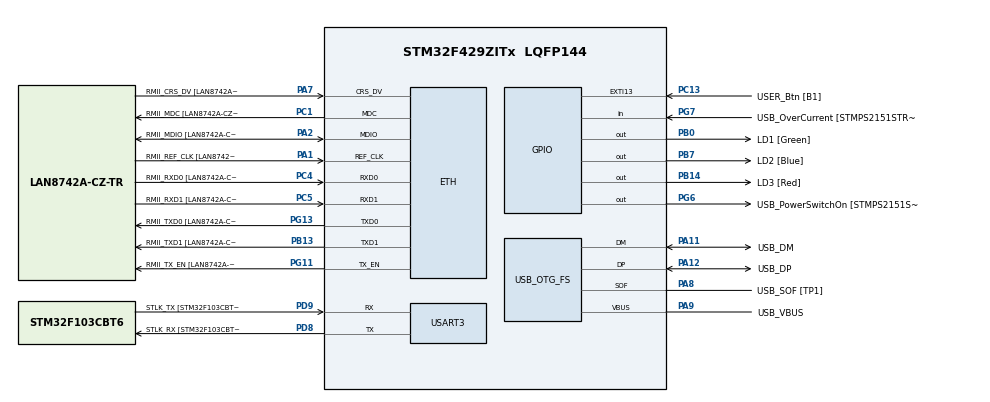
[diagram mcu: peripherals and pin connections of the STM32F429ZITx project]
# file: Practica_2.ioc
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ETH.MediaInterface=HAL_ETH_RMII_MODE
ETH.PHY_Name=LAN8742A_PHY_ADDRESS
ETH.PHY_Value=0
ETH.PhyAddress=0
Mcu.Family=STM32F4
Mcu.Name=STM32F429ZITx
Mcu.Package=LQFP144
NVIC.PriorityGroup=NVIC_PRIORITYGROUP_4
PA1.GPIO_Label=RMII_REF_CLK [LAN8742A-CZ-TR_REFCLK0]
PA1.Mode=RMII
PA1.Signal=ETH_REF_CLK
PA10.GPIO_Label=USB_ID
PA10.Signal=USB_OTG_FS_ID
PA11.GPIO_Label=USB_DM
PA11.Mode=Device_Only
PA11.Signal=USB_OTG_FS_DM
PA12.GPIO_Label=USB_DP
PA12.Mode=Device_Only
PA12.Signal=USB_OTG_FS_DP
PA13.GPIO_Label=TMS
PA13.Mode=Serial_Wire
PA13.Signal=SYS_JTMS-SWDIO
PA14.GPIO_Label=TCK
PA14.Mode=Serial_Wire
PA14.Signal=SYS_JTCK-SWCLK
PA2.GPIO_Label=RMII_MDIO [LAN8742A-CZ-TR_MDIO]
PA2.Mode=RMII
PA2.Signal=ETH_MDIO
PA7.GPIO_Label=RMII_CRS_DV [LAN8742A-CZ-TR_CRS_DV]
PA7.Mode=RMII
PA7.Signal=ETH_CRS_DV
PA8.GPIO_Label=USB_SOF [TP1]
PA8.Mode=Activate_SOF_FS
PA8.Signal=USB_OTG_FS_SOF
PA9.GPIO_Label=USB_VBUS
PA9.Mode=Activate_VBUS
PA9.Signal=USB_OTG_FS_VBUS
PB0.GPIO_Label=LD1 [Green]
PB0.Signal=GPIO_Output
PB13.GPIO_Label=RMII_TXD1 [LAN8742A-CZ-TR_TXD1]
PB13.Mode=RMII
PB13.Signal=ETH_TXD1
PB14.GPIO_Label=LD3 [Red]
PB14.Signal=GPIO_Output
PB7.GPIO_Label=LD2 [Blue]
PB7.Signal=GPIO_Output
PC1.GPIO_Label=RMII_MDC [LAN8742A-CZ-TR_MDC]
PC1.Mode=RMII
PC1.Signal=ETH_MDC
PC13.GPIO_Label=USER_Btn [B1]
PC13.Signal=GPXTI13
PC14/OSC32_IN.Mode=LSE-External-Oscillator
PC14/OSC32_IN.Signal=RCC_OSC32_IN
PC15/OSC32_OUT.Mode=LSE-External-Oscillator
PC15/OSC32_OUT.Signal=RCC_OSC32_OUT
PC4.GPIO_Label=RMII_RXD0 [LAN8742A-CZ-TR_RXD0]
PC4.Mode=RMII
PC4.Signal=ETH_RXD0
PC5.GPIO_Label=RMII_RXD1 [LAN8742A-CZ-TR_RXD1]
PC5.Mode=RMII
PC5.Signal=ETH_RXD1
PD8.GPIO_Label=STLK_RX [STM32F103CBT6_PA3]
PD8.Mode=Asynchronous
PD8.Signal=USART3_TX
PD9.GPIO_Label=STLK_TX [STM32F103CBT6_PA2]
PD9.Mode=Asynchronous
PD9.Signal=USART3_RX
PG11.GPIO_Label=RMII_TX_EN [LAN8742A-CZ-TR_TXEN]
PG11.Mode=RMII
PG11.Signal=ETH_TX_EN
PG13.GPIO_Label=RMII_TXD0 [LAN8742A-CZ-TR_TXD0]
PG13.Mode=RMII
PG13.Signal=ETH_TXD0
PG6.GPIO_Label=USB_PowerSwitchOn [STMPS2151STR_EN]
PG6.Signal=GPIO_Output
PG7.GPIO_Label=USB_OverCurrent [STMPS2151STR_FAULT]
PG7.Signal=GPIO_Input
PH0/OSC_IN.Mode=HSE-External-Clock-Source
PH0/OSC_IN.Signal=RCC_OSC_IN
PH1/OSC_OUT.Mode=HSE-External-Clock-Source
PH1/OSC_OUT.Signal=RCC_OSC_OUT
ProjectManager.HeapSize=0x200
ProjectManager.StackSize=0x400
ProjectManager.TargetToolchain=STM32CubeIDE
RCC.48MHZClocksFreq_Value=48000000
RCC.AHBFreq_Value=168000000
RCC.APB1Freq_Value=42000000
RCC.APB1TimFreq_Value=42000000
RCC.APB2Freq_Value=84000000
RCC.APB2TimFreq_Value=84000000
RCC.CortexFreq_Value=168000000
RCC.HCLKFreq_Value=168000000
RCC.HSE_VALUE=8000000
RCC.SYSCLKFreq_VALUE=168000000
RCC.SYSCLKSource=RCC_SYSCLKSOURCE_PLLCLK
RCC.VCOOutputFreq_Value=336000000
USART3.VirtualMode=VM_ASYNC
USB_OTG_FS.VirtualMode=Device_Only
board=NUCLEO-F429ZI

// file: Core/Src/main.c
/* USER CODE BEGIN Header */
/**
  ******************************************************************************
  * @file           : main.c
  * @brief          : Main program body
  ******************************************************************************
  * @attention
  *
  * Copyright (c) 2023 STMicroelectronics.
  * All rights reserved.
  *
  * This software is licensed under terms that can be found in the LICENSE file
  * in the root directory of this software component.
  * If no LICENSE file comes with this software, it is provided AS-IS.
  *
  ******************************************************************************
  */
/* USER CODE END Header */
#include "main.h"
#include "string.h"

/* USER CODE BEGIN PTD */
typedef void (*patternCallback)(void);

/**
 * @brief Struct que describe un patrón de ejecución de un timer.
 */
typedef struct{
	uint16_t repeats; 				/*!< Define cuantas veces se ejecuta el patrón hasta dar done  */
	uint16_t currentCicle;			/*!< Cuantas veces se ejecuto el ciclo */
	uint32_t interval;				/*!< Tiempo total que dura cada repetición  */
	uint8_t dutyCicle;				/*!< Porcentaje de interval hasta ejecutar callback_off. Maximo 99   */
	delay_t * delay;				/*!< controlador de tiempo para el generador de patrones  */
	bool done;						/*!< Indica que el patrón se ejecutó completo   */
	bool off_period;				/*!< Indica que el patron está ejecutando el ciclo off   */
	patternCallback callbackOff;	/*!< Función a ejecutar cuando trascurre un tiempo interval*dutyCicle   */
	patternCallback callbackOn;		/*!< Función a ejecutar apenas inicia un ciclo   */
} TimerPattern_t;
/* USER CODE END PTD */

ETH_TxPacketConfig TxConfig;
ETH_DMADescTypeDef  DMARxDscrTab[ETH_RX_DESC_CNT]; /* Ethernet Rx DMA Descriptors */
ETH_DMADescTypeDef  DMATxDscrTab[ETH_TX_DESC_CNT]; /* Ethernet Tx DMA Descriptors */

ETH_HandleTypeDef heth;

UART_HandleTypeDef huart3;

PCD_HandleTypeDef hpcd_USB_OTG_FS;

/* USER CODE BEGIN PV */
/**
 * Apunto el puntero a función getCurrentTick a la función que me interesa en este target.
 */
GetCurrentTick_t getCurrentTick = HAL_GetTick;
delay_t delayLed = {0};
TimerPattern_t testPattern1 = {0};
TimerPattern_t testPattern2 = {0};
TimerPattern_t testPattern3 = {0};
/* USER CODE END PV */

void SystemClock_Config(void);
static void MX_GPIO_Init(void);
static void MX_ETH_Init(void);
static void MX_USART3_UART_Init(void);
static void MX_USB_OTG_FS_PCD_Init(void);
/* USER CODE BEGIN PFP */

/**
  * @brief  Inicializa una secuencia de timer
  * @param pattern Puntero a estrucutra TimePattern_t
  * @param delay Puntero a instancia de delay para usar en el patrón.
  * @param repeats La cantidad de ciclos que se repite la secuencia.
  * @param interval el tiempo de duración total de cada ciclo
  * @param Duty dicle del periodo On.
  * @param callbackOff Función llamaba cuando expire el periodo Off.
  * @param callbackOn Función llamaba cuando inica cada ciclo.
  * @retval None
  */
void patternInit(TimerPattern_t* pattern,delay_t* delay,uint16_t repeats,uint32_t interval, uint8_t dutyCicle, patternCallback callbackOff, patternCallback callbackOn);

/**
  * @brief  Ejecuta una secuencia.
  * @note 	Esta función es thread safe porque guardo todo en el TimerPattern_t.
  * @param pattern Puntero a estrucutra TimePattern_t
  * @retval true La secuencia finalizó
  * @retval false La secuencia no finalizó
  */
bool patternRun(TimerPattern_t* pattern);

/**
  * @brief  Ejecuta en orden las secuencias en un array.
  * @note	Era más fácil el código si tomaba un array de punteros a las estrucutras. Como para poder aceptar arrays de cualquier tamaño tengo que aceptar punteros
  * 		del mismo tipo (osea, puntero a TimerPattern_t), me termina quedando un puntero de puntero a TimerPattern_t.
  * 		Esta función _no_ es thread safe (uso una variable estática).
  * @param collection Puntero a array de patrones.
  * @param size Tamaño de la colección.
  * @retval true La secuencia finalizó
  * @retval false La secuencia no finalizó
  */
bool patternCollectionRun(TimerPattern_t ** collection, size_t size, bool continuous);

/**
  * @brief  Versión thread safe de patternCollectionRun.
  * @param collection Puntero a array de patrones.
  * @param size Tamaño de la colección.
  * @param index Puntero al índice del patrón en ejecución.
  * @retval true La secuencia finalizó
  * @retval false La secuencia no finalizó
  */
bool patternCollectionRun_s(TimerPattern_t ** collection, size_t size, bool continuous, uint8_t* index );

void patternRestart(TimerPattern_t* pattern);

/* USER CODE END PFP */

/* USER CODE BEGIN 0 */
void testPatternCallback(void){
	HAL_GPIO_TogglePin(GPIOB, LD1_Pin);
}
/* USER CODE END 0 */

int main(void)
{

  /* MCU Configuration--------------------------------------------------------*/

  /* Reset of all peripherals, Initializes the Flash interface and the Systick. */
  HAL_Init();

  /* Configure the system clock */
  SystemClock_Config();

  /* Initialize all configured peripherals */
  MX_GPIO_Init();
  MX_ETH_Init();
  MX_USART3_UART_Init();
  MX_USB_OTG_FS_PCD_Init();
  /* USER CODE BEGIN 2 */

  delayInit(&delayLed, 100, false);
  patternInit(&testPattern1,&delayLed,5,1000,50,testPatternCallback,testPatternCallback);
  patternInit(&testPattern2,&delayLed,5,200,50,testPatternCallback,testPatternCallback);
  patternInit(&testPattern3,&delayLed,5,100,50,testPatternCallback,testPatternCallback);

  TimerPattern_t* patternArray[3] = {&testPattern1,&testPattern2,&testPattern3};

  /* USER CODE END 2 */

  /* Infinite loop */
  while (1)
  {
	  patternCollectionRun(patternArray,3,true);
  }
}

void SystemClock_Config(void)
{
  RCC_OscInitTypeDef RCC_OscInitStruct = {0};
  RCC_ClkInitTypeDef RCC_ClkInitStruct = {0};

  /** Configure the main internal regulator output voltage
  */
  __HAL_RCC_PWR_CLK_ENABLE();
  __HAL_PWR_VOLTAGESCALING_CONFIG(PWR_REGULATOR_VOLTAGE_SCALE1);

  /** Initializes the RCC Oscillators according to the specified parameters
  * in the RCC_OscInitTypeDef structure.
  */
  RCC_OscInitStruct.OscillatorType = RCC_OSCILLATORTYPE_HSE;
  RCC_OscInitStruct.HSEState = RCC_HSE_BYPASS;
  RCC_OscInitStruct.PLL.PLLState = RCC_PLL_ON;
  RCC_OscInitStruct.PLL.PLLSource = RCC_PLLSOURCE_HSE;
  RCC_OscInitStruct.PLL.PLLM = 16;
  RCC_OscInitStruct.PLL.PLLN = 192;
  RCC_OscInitStruct.PLL.PLLP = RCC_PLLP_DIV2;
  RCC_OscInitStruct.PLL.PLLQ = 4;
  if (HAL_RCC_OscConfig(&RCC_OscInitStruct) != HAL_OK)
  {
    Error_Handler();
  }

  /** Initializes the CPU, AHB and APB buses clocks
  */
  RCC_ClkInitStruct.ClockType = RCC_CLOCKTYPE_HCLK|RCC_CLOCKTYPE_SYSCLK
                              |RCC_CLOCKTYPE_PCLK1|RCC_CLOCKTYPE_PCLK2;
  RCC_ClkInitStruct.SYSCLKSource = RCC_SYSCLKSOURCE_PLLCLK;
  RCC_ClkInitStruct.AHBCLKDivider = RCC_SYSCLK_DIV1;
  RCC_ClkInitStruct.APB1CLKDivider = RCC_HCLK_DIV1;
  RCC_ClkInitStruct.APB2CLKDivider = RCC_HCLK_DIV1;

  if (HAL_RCC_ClockConfig(&RCC_ClkInitStruct, FLASH_LATENCY_5) != HAL_OK)
  {
    Error_Handler();
  }
}

static void MX_ETH_Init(void)
{

   static uint8_t MACAddr[6];

  heth.Instance = ETH;
  MACAddr[0] = 0x00;
  MACAddr[1] = 0x80;
  MACAddr[2] = 0xE1;
  MACAddr[3] = 0x00;
  MACAddr[4] = 0x00;
  MACAddr[5] = 0x00;
  heth.Init.MACAddr = &MACAddr[0];
  heth.Init.MediaInterface = HAL_ETH_RMII_MODE;
  heth.Init.TxDesc = DMATxDscrTab;
  heth.Init.RxDesc = DMARxDscrTab;
  heth.Init.RxBuffLen = 1524;

  if (HAL_ETH_Init(&heth) != HAL_OK)
  {
    Error_Handler();
  }

  memset(&TxConfig, 0 , sizeof(ETH_TxPacketConfig));
  TxConfig.Attributes = ETH_TX_PACKETS_FEATURES_CSUM | ETH_TX_PACKETS_FEATURES_CRCPAD;
  TxConfig.ChecksumCtrl = ETH_CHECKSUM_IPHDR_PAYLOAD_INSERT_PHDR_CALC;
  TxConfig.CRCPadCtrl = ETH_CRC_PAD_INSERT;

}

static void MX_USART3_UART_Init(void)
{

  huart3.Instance = USART3;
  huart3.Init.BaudRate = 115200;
  huart3.Init.WordLength = UART_WORDLENGTH_8B;
  huart3.Init.StopBits = UART_STOPBITS_1;
  huart3.Init.Parity = UART_PARITY_NONE;
  huart3.Init.Mode = UART_MODE_TX_RX;
  huart3.Init.HwFlowCtl = UART_HWCONTROL_NONE;
  huart3.Init.OverSampling = UART_OVERSAMPLING_16;
  if (HAL_UART_Init(&huart3) != HAL_OK)
  {
    Error_Handler();
  }

}

static void MX_USB_OTG_FS_PCD_Init(void)
{

  hpcd_USB_OTG_FS.Instance = USB_OTG_FS;
  hpcd_USB_OTG_FS.Init.dev_endpoints = 4;
  hpcd_USB_OTG_FS.Init.speed = PCD_SPEED_FULL;
  hpcd_USB_OTG_FS.Init.dma_enable = DISABLE;
  hpcd_USB_OTG_FS.Init.phy_itface = PCD_PHY_EMBEDDED;
  hpcd_USB_OTG_FS.Init.Sof_enable = ENABLE;
  hpcd_USB_OTG_FS.Init.low_power_enable = DISABLE;
  hpcd_USB_OTG_FS.Init.lpm_enable = DISABLE;
  hpcd_USB_OTG_FS.Init.vbus_sensing_enable = ENABLE;
  hpcd_USB_OTG_FS.Init.use_dedicated_ep1 = DISABLE;
  if (HAL_PCD_Init(&hpcd_USB_OTG_FS) != HAL_OK)
  {
    Error_Handler();
  }

}

static void MX_GPIO_Init(void)
{
  GPIO_InitTypeDef GPIO_InitStruct = {0};

  /* GPIO Ports Clock Enable */
  __HAL_RCC_GPIOC_CLK_ENABLE();
  __HAL_RCC_GPIOH_CLK_ENABLE();
  __HAL_RCC_GPIOA_CLK_ENABLE();
  __HAL_RCC_GPIOB_CLK_ENABLE();
  __HAL_RCC_GPIOD_CLK_ENABLE();
  __HAL_RCC_GPIOG_CLK_ENABLE();

  /*Configure GPIO pin Output Level */
  HAL_GPIO_WritePin(GPIOB, LD1_Pin|LD3_Pin|LD2_Pin, GPIO_PIN_RESET);

  /*Configure GPIO pin Output Level */
  HAL_GPIO_WritePin(USB_PowerSwitchOn_GPIO_Port, USB_PowerSwitchOn_Pin, GPIO_PIN_RESET);

  /*Configure GPIO pin : USER_Btn_Pin */
  GPIO_InitStruct.Pin = USER_Btn_Pin;
  GPIO_InitStruct.Mode = GPIO_MODE_IT_RISING;
  GPIO_InitStruct.Pull = GPIO_NOPULL;
  HAL_GPIO_Init(USER_Btn_GPIO_Port, &GPIO_InitStruct);

  /*Configure GPIO pins : LD1_Pin LD3_Pin LD2_Pin */
  GPIO_InitStruct.Pin = LD1_Pin|LD3_Pin|LD2_Pin;
  GPIO_InitStruct.Mode = GPIO_MODE_OUTPUT_PP;
  GPIO_InitStruct.Pull = GPIO_NOPULL;
  GPIO_InitStruct.Speed = GPIO_SPEED_FREQ_LOW;
  HAL_GPIO_Init(GPIOB, &GPIO_InitStruct);

  /*Configure GPIO pin : USB_PowerSwitchOn_Pin */
  GPIO_InitStruct.Pin = USB_PowerSwitchOn_Pin;
  GPIO_InitStruct.Mode = GPIO_MODE_OUTPUT_PP;
  GPIO_InitStruct.Pull = GPIO_NOPULL;
  GPIO_InitStruct.Speed = GPIO_SPEED_FREQ_LOW;
  HAL_GPIO_Init(USB_PowerSwitchOn_GPIO_Port, &GPIO_InitStruct);

  /*Configure GPIO pin : USB_OverCurrent_Pin */
  GPIO_InitStruct.Pin = USB_OverCurrent_Pin;
  GPIO_InitStruct.Mode = GPIO_MODE_INPUT;
  GPIO_InitStruct.Pull = GPIO_NOPULL;
  HAL_GPIO_Init(USB_OverCurrent_GPIO_Port, &GPIO_InitStruct);

}

/* USER CODE BEGIN 4 */
void delayInit( delay_t * delay, tick_t duration, bool_t singleShot ){
	delay->startTime= 0;
	delay->running = false;
	delay->singleShot = singleShot;
	delay->duration = duration;
	if(delay->singleShot) delay->enabled=false;
	else delay->enabled = true;
	return;
}

bool_t delayRead( delay_t * delay ){
	if(delay->enabled == false) return false;
	if(delay->running == false){
		delay->startTime = getCurrentTick();
		delay->running = true;
		return false;
	}
	else{
		/**
		 * - Uso mayor o igual, porque con este mecanismo de "polling" al delay, es muy dificil pegarle justo al tiempo establecido.
		 * - getCurretTick() normalmente devolvería un número mayor a startTime, excepto justo después de un overflow del tipo uint32.
		 * 	Esto tal vez sugiera el uso de abs, pero no hace falta: la resta complemento a 1 con tipos unsigned da correctamente la distancias entre números.
		 * 	La excepción, y donde esto falla, es si delayRead se ejecuta después de una vuelta entera del uint32 (después de 1193 horas), más un poquito por encima
		 * 	de startTime, pero sin llegar a que la resta dé mayor a duration, con lo que como mucho este método puede tener un error de duration.
		 */
		if(getCurrentTick() - delay->startTime >= delay->duration){
			delay->running = false;
			if(delay->singleShot) delay->enabled=false;
			return true;
		}
		else return false;
	}
}

void delayWrite( delay_t * delay, tick_t duration, bool_t restart){
	delay->duration = duration;
	if(restart){
		delay->running = false;
		delayRead(delay);
	}
}

void delayStart(delay_t * delay){
	delay->enabled = true;
}

void delatStop(delay_t * delay){
	delay->enabled = false;
}

void patternInit(TimerPattern_t* pattern,delay_t* delay,uint16_t repeats,uint32_t interval, uint8_t dutyCicle, patternCallback callbackOff, patternCallback callbackOn){
	if(dutyCicle > 99) dutyCicle = 99;
	pattern->callbackOff = callbackOff;
	pattern->callbackOn = callbackOn;
	pattern->interval = interval;
	pattern->repeats = repeats;
	pattern->delay = delay;
	pattern->done = false;
	pattern->dutyCicle = dutyCicle;
	pattern->currentCicle = 0;
	pattern->off_period = false;
	interval = (uint32_t)((interval * dutyCicle)/100);
	delayInit(delay,interval,false);
}

bool patternRun(TimerPattern_t* pattern){
	if(pattern->done) return true;
	if(pattern->currentCicle == pattern->repeats){
		pattern->done = true;
		return true;
	}
	if(!pattern->delay->running) {
		pattern->callbackOn();
		uint8_t dutycicle = pattern->dutyCicle;
		if(dutycicle > 99) dutycicle = 99;
		delayWrite(pattern->delay, (uint32_t)((pattern->interval*(dutycicle))/100), true );
	}
	if(delayRead(pattern->delay)){
		if(!pattern->off_period){
			pattern->callbackOff();
			pattern->off_period = true;
			uint8_t dutycicle = pattern->dutyCicle;
			if(dutycicle > 99) dutycicle = 99;
			delayWrite(pattern->delay, (uint32_t)((pattern->interval*(100-dutycicle))/100), true );
			return false;
		}
		else{
			pattern->off_period = false;
			pattern->currentCicle++;
			return false;
		}
	}
	else{
		return false;
	}
}

void patternRestart(TimerPattern_t* pattern){
	pattern->done = false;
	pattern->currentCicle = 0;
}

bool patternCollectionRun_s(TimerPattern_t ** collection, size_t size, bool continuous, uint8_t* index) {
	if(*index >= size) return true;
	if(patternRun(collection[*index])){
		patternRestart(collection[*index]);
		*index = *index + 1;
		if(*index >= size) {
			if(continuous) *index = 0;
			return true;
		}
		else return false;
	}
	else return false;
}

bool patternCollectionRun(TimerPattern_t ** collection, size_t size, bool continuous) {
	static uint8_t index;
	return patternCollectionRun_s(collection,size,continuous,&index);
}
/* USER CODE END 4 */

void Error_Handler(void)
{
  __disable_irq();
  while (1)
  {
  }
}
